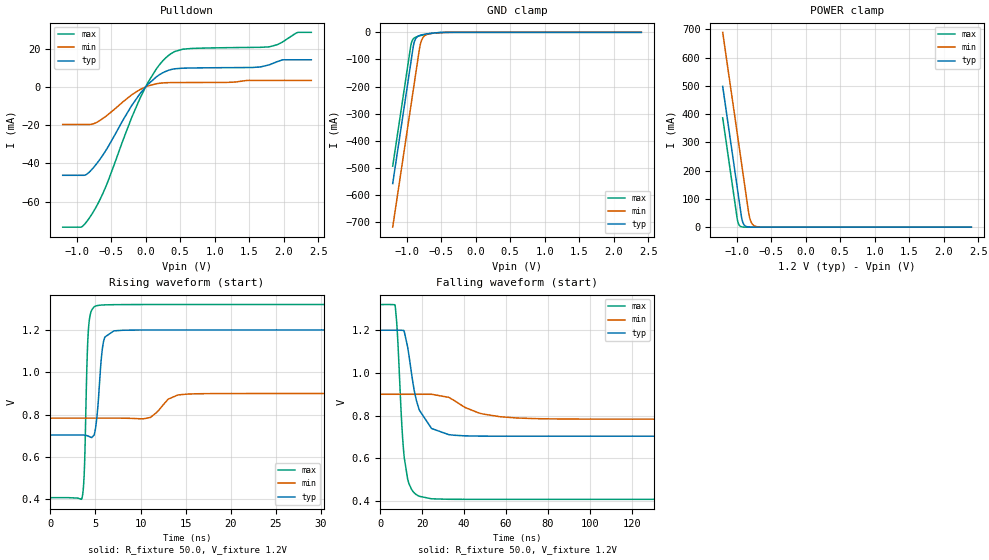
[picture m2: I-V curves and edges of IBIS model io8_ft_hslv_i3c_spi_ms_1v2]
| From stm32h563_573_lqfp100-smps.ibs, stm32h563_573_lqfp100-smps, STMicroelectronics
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[Model]   io8_ft_hslv_i3c_spi_ms_1v2
Model_type I/O_open_drain
Polarity   Non-Inverting
Enable   Active-Low
| CAP_THRESHOLD on pad IOFT is "UDTCAPC" :
| Rising=20.0% of vddiom   Falling=80.0% of vddiom
| C_comp min and max val. don't necessarily correlate with the min and max pvt
| but are the smallest and greatest pad capacitance found.
| var   typ   min   max
C_comp   3.41800pF  3.39985pF  3.42900pF
|C_comp_pulldown   3.41800pF  3.39985pF  3.42900pF
Vinl = 450.0mV
Vinh = 660.0mV
Vmeas = 600.0mV   | Reference voltage for timing measurements
Cref  = 50.0pF   | Timing specification test load capacitance value
Rref  = 1.0MOhm   | Timing specification test load resistance value
Vref  = 660.0mV   | Timing specification test load voltage
[Model Spec]
| TIME_THRESHOLD on pin ZII2CV11 is "CMOS" :
| Rising=40.0% of vdd   Falling=60.0% of vdd
Vinl 447.80000mV 344.80000mV 489.80000mV
Vinh 733.20000mV 535.20000mV 813.20000mV
| variable   typ   min   max
[Temperature Range] 25.0 125.0 -40.0
| variable   typ   min   max
[Voltage Range] 1.2V 900.0mV 1.32V
| variable   typ   min   max
[POWER Clamp Reference] 1.2V 900.0mV 1.32V
| variable   typ   min   max
[GND Clamp Reference] 0V 0V 0V
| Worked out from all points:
|   slope of the pulldown table from 0 to 0.18 V, typ, clamps not added: 30.6 ohm
|   GND clamp passes 1 mA (typ) near -0.52 V on its own axis
|   POWER clamp passes 1 mA (typ) near -0.84 V on its own axis
|   rising waveform, R_fixture 50.0, V_fixture 1.2V: 20-80 % time 543ps typ, 1.57ns min, 328ps max; typ from 0.704 V to 1.2 V
|   falling waveform, R_fixture 50.0, V_fixture 1.2V: 20-80 % time 6.81ns typ, 15.3ns min, 3.22ns max; typ from 1.2 V to 0.704 V
[POWER Clamp]
-1.2V     497.8mA    689.2mA    386.5mA
-990mV    140.8mA    332.2mA    29.53mA
-980mV    123.8mA    315.2mA    17.95mA
-960mV    89.81mA    281.2mA    6.634mA
-930mV    38.81mA    230.2mA    1.49mA
-900mV    12.07mA    179.2mA    334.8uA
-870mV    3.756mA    128.2mA    75.22uA
-820mV    536.4uA    44.98mA    6.246uA
-790mV    166.9uA    18.76mA    1.403uA
-750mV    35.18uA    5.846mA    191.8nA
-590mV    70.09nA    55uA       165.5pA
2.4V      0A         0A         0A
[GND Clamp]
-1.2V     -558.2mA   -719mA     -494.1mA
-940mV    -116.2mA   -277mA     -52.06mA
-930mV    -99.19mA   -260mA     -39.94mA
-900mV    -49.1mA    -209mA     -23.76mA
-880mV    -30.14mA   -175mA     -19.6mA
-850mV    -17.82mA   -124mA     -16.09mA
-810mV    -11.73mA   -56.78mA   -12.91mA
-780mV    -9.444mA   -28.21mA   -10.92mA
-740mV    -7.291mA   -13.16mA   -8.574mA
-640mV    -3.573mA   -4.171mA   -3.954mA
-380mV    -61.75uA   -230.3uA   -20.32uA
2.4V      3.863nA    718.4nA    150.6pA
| variable   typ   min   max
[Pullup Reference] 1.2V 900.0mV 1.32V
| variable   typ   min   max
[Pulldown Reference] 0V 0V 0V
[Pulldown]
-1.2V     -46.17mA   -19.62mA   -73.27mA
-930mV    -46.17mA   -19.62mA   -73.18mA
-770mV    -42.8mA    -19.41mA   -66.04mA
-570mV    -32.88mA   -15.18mA   -51.58mA
-80mV     -3.488mA   -1.363mA   -5.887mA
160mV     5.368mA    1.686mA    9.621mA
340mV     8.782mA    2.251mA    16.66mA
540mV     9.805mA    2.305mA    19.74mA
1.79V     11.53mA    3.428mA    20.94mA
1.98V     14.11mA    3.428mA    23.43mA
2.2V      14.2mA     3.428mA    28.44mA
2.4V      14.2mA     3.428mA    28.54mA
[Ramp]
dV/dt_r 297.78941mV/542.92947ps 69.89228mV/1.49795ns 547.1275mV/326.08305ps
dV/dt_f 297.80517mV/6.15576ns 69.92038mV/15.00937ns 547.13932mV/3.15836ns
R_load = 50.0
| Removed startup time: 0s 0s 0s  .
| Removed end time: 49.4ns.
[Rising Waveform]
R_fixture   = 50.0
V_fixture   = 1.2V
V_fixture_min = 900.0mV
V_fixture_max = 1.32V
0s        703.7mV    783.5mV    408.1mV
3.55ns    703.8mV    783.5mV    412.2mV
3.8ns     703.2mV    783.5mV    565.1mV
4.05ns    701.1mV    783.5mV    1.018V
4.2ns     698.8mV    783.5mV    1.184V
5ns       731.9mV    783.5mV    1.312V
5.85ns    1.133V     783.5mV    1.318V
7.05ns    1.196V     783.5mV    1.319V
15.15ns   1.2V       896.9mV    1.32V
49.4ns    1.2V       900mV      1.32V
| Removed startup time: 0s 0s 0s  .
| Removed end time: 399.4ns.
[Falling Waveform]
R_fixture   = 50.0
V_fixture   = 1.2V
V_fixture_min = 900.0mV
V_fixture_max = 1.32V
0s        1.2V       900mV      1.32V
7.05ns    1.2V       900mV      1.317V
8.05ns    1.2V       900mV      1.203V
10.15ns   1.2V       900mV      777.9mV
11.45ns   1.193V     900mV      602.3mV
13.75ns   1.077V     900mV      479.5mV
18.55ns   827.1mV    900mV      422.4mV
24.45ns   739.8mV    900mV      410.5mV
40.75ns   705.3mV    836.9mV    408.1mV
399.4ns   703.7mV    783.5mV    408.1mV
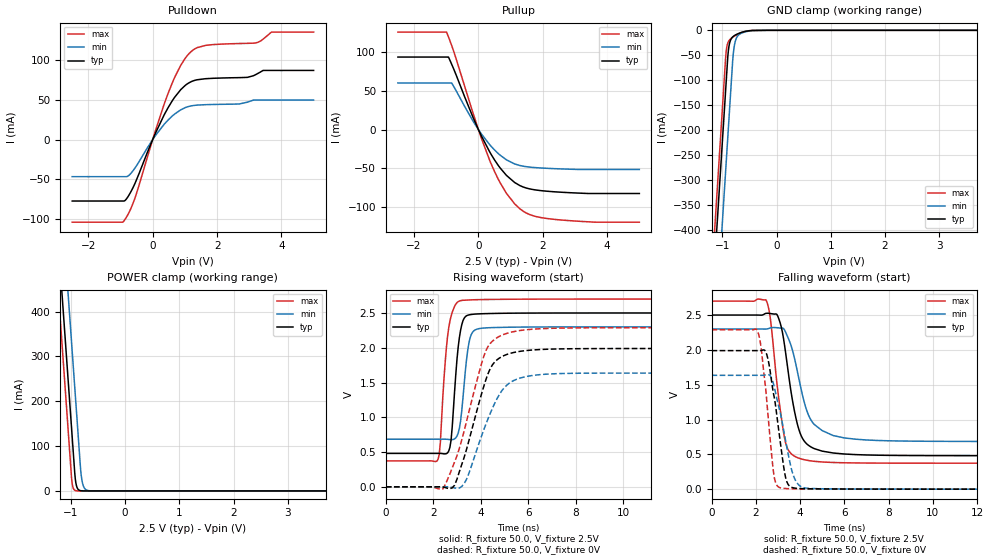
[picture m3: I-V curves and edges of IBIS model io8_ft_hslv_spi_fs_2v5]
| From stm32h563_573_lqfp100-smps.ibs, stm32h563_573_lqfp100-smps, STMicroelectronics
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[Model]   io8_ft_hslv_spi_fs_2v5
Model_type I/O
Polarity   Non-Inverting
Enable   Active-Low
| CAP_THRESHOLD on pad IOFT is "UDTCAPC" :
| Rising=20.0% of vddiom   Falling=80.0% of vddiom
| C_comp min and max val. don't necessarily correlate with the min and max pvt
| but are the smallest and greatest pad capacitance found.
| var   typ   min   max
C_comp   4.85188pF  4.77592pF  4.93402pF
|C_comp_pullup   3.10525pF  2.91265pF  2.94055pF
|C_comp_pulldown   1.74663pF  1.86327pF  1.99347pF
Vinl = 690.0mV
Vinh = 1.89V
Vmeas = 1.25V   | Reference voltage for timing measurements
Cref  = 50.0pF   | Timing specification test load capacitance value
Rref  = 100.0MOhm   | Timing specification test load resistance value
Vref  = 1.25V   | Timing specification test load voltage
[Model Spec]
| TIME_THRESHOLD on pin ZIV11 is "CMOS" :
| Rising=40.0% of vdd   Falling=60.0% of vdd
Vinl 989.80000mV 917.80000mV 1.06580V
Vinh 1.40320V 1.29620V 1.49120V
| variable   typ   min   max
[Temperature Range] 25.0 125.0 -40.0
| variable   typ   min   max
[Voltage Range] 2.5V 2.3V 2.7V
| variable   typ   min   max
[POWER Clamp Reference] 2.5V 2.3V 2.7V
| variable   typ   min   max
[GND Clamp Reference] 0V 0V 0V
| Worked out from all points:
|   slope of the pulldown table from 0 to 0.375 V, typ, clamps not added: 11.5 ohm
|   slope of the pullup table from 0 to 0.375 V, typ, clamps not added: 12.3 ohm
|   GND clamp passes 1 mA (typ) near -0.52 V on its own axis
|   POWER clamp passes 1 mA (typ) near -0.84 V on its own axis
|   rising waveform, R_fixture 50.0, V_fixture 2.5V: 20-80 % time 279ps typ, 288ps min, 300ps max; typ from 0.481 V to 2.5 V
|   falling waveform, R_fixture 50.0, V_fixture 2.5V: 20-80 % time 637ps typ, 796ps min, 509ps max; typ from 2.5 V to 0.481 V
|   rising waveform, R_fixture 50.0, V_fixture 0V: 20-80 % time 995ps typ, 1.12ns min, 1.08ns max; typ from 0 V to 1.99 V
|   falling waveform, R_fixture 50.0, V_fixture 0V: 20-80 % time 531ps typ, 636ps min, 417ps max; typ from 1.99 V to 0 V
[POWER Clamp]
-2.5V     2.708A     2.899A     2.597A
-1.23V    548.8mA    740.2mA    437.5mA
-1.16V    429.8mA    621.2mA    318.5mA
-1.07V    276.8mA    468.2mA    165.5mA
-1.03V    208.8mA    400.2mA    97.53mA
-980mV    123.8mA    315.2mA    17.95mA
-920mV    26.3mA     213.2mA    906uA
-880mV    5.543mA    145.2mA    123.7uA
-810mV    363.5uA    33.6mA     3.797uA
-770mV    76.62uA    10.47mA    518.9nA
-700mV    5.026uA    1.361mA    16.14nA
5V        0A         0A         0A
[GND Clamp]
-2.5V     -2.771A    -2.933A    -2.706A
-1.21V    -578.3mA   -739.7mA   -512.8mA
-950mV    -136.3mA   -297.7mA   -70.75mA
-930mV    -102.3mA   -263.7mA   -41.56mA
-900mV    -51.97mA   -212.7mA   -25.14mA
-880mV    -32.59mA   -178.7mA   -20.84mA
-850mV    -19.78mA   -127.7mA   -17.15mA
-810mV    -13.22mA   -60.17mA   -13.75mA
-780mV    -10.64mA   -30.96mA   -11.62mA
-730mV    -7.637mA   -13.21mA   -8.533mA
-430mV    -217.7uA   -562.2uA   -113.2uA
5V        7.27nA     1.305uA    342.4pA
| variable   typ   min   max
[Pullup Reference] 2.5V 2.3V 2.7V
| variable   typ   min   max
[Pulldown Reference] 0V 0V 0V
[Pullup]
-2.5V     93.6mA     60.17mA    125.8mA
-990mV    93.6mA     60.17mA    125.8mA
-930mV    93.6mA     60.17mA    119.6mA
-830mV    84.26mA    60.17mA    108.5mA
-170mV    16.03mA    11.13mA    21.65mA
350mV     -28.74mA   -19.44mA   -39.66mA
610mV     -45.85mA   -30.67mA   -63.5mA
870mV     -59.1mA    -39.02mA   -82.25mA
1.29V     -72.3mA    -46.39mA   -102.3mA
1.7V      -77.4mA    -48.84mA   -111.2mA
2.27V     -80.02mA   -50.27mA   -115.5mA
5V        -82.5mA    -51.48mA   -119.5mA
[Pulldown]
-2.5V     -77.63mA   -46.84mA   -104.3mA
-870mV    -77.25mA   -46.84mA   -101.4mA
-550mV    -55.3mA    -35.88mA   -73.72mA
90mV      8.401mA    5.299mA    11.79mA
610mV     49.03mA    29.76mA    71.69mA
870mV     62.92mA    37.48mA    93.62mA
1.23V     73.63mA    42.72mA    112.2mA
1.64V     76.78mA    44.01mA    118.8mA
2.94V     78.48mA    47.15mA    121.4mA
3.24V     82.82mA    49.81mA    122.4mA
3.69V     87.21mA    49.81mA    135.6mA
5V        87.21mA    49.81mA    135.6mA
[Ramp]
dV/dt_r 1.19345V/991.96714ps 980.81039mV/1.1152ns 1.37306V/1.07487ns
dV/dt_f 1.21165V/635.80001ps 969.25611mV/793.88244ps 1.39628V/507.94681ps
R_load = 50.0
| Removed startup time: 0s 0s 0s  .
| Removed end time: 14.4ns.
[Rising Waveform]
R_fixture   = 50.0
V_fixture   = 2.5V
V_fixture_min = 2.3V
V_fixture_max = 2.7V
0s        480.6mV    684.6mV    372.9mV
2.2ns     480.8mV    684.7mV    393.8mV
2.3ns     480.9mV    684.8mV    643.3mV
2.55ns    476.5mV    684.3mV    1.988V
2.7ns     566.2mV    679.1mV    2.381V
3.1ns     2.143V     838mV      2.672V
3.25ns    2.387V     1.271V     2.682V
3.5ns     2.472V     2.063V     2.687V
3.8ns     2.485V     2.262V     2.691V
14.4ns    2.5V       2.3V       2.7V
| Removed startup time: 0s 0s 0s  .
| Removed end time: 24.4ns.
[Falling Waveform]
R_fixture   = 50.0
V_fixture   = 2.5V
V_fixture_min = 2.3V
V_fixture_max = 2.7V
0s        2.5V       2.3V       2.7V
2.45ns    2.524V     2.299V     2.719V
2.65ns    2.522V     2.315V     2.466V
2.95ns    2.51V      2.318V     1.53V
3.3ns     2.062V     2.284V     730.3mV
3.7ns     1.197V     1.942V     482.9mV
4.05ns    766.9mV    1.432V     434.3mV
4.65ns    581.1mV    926.2mV    399.8mV
6.5ns     496.3mV    717.4mV    376.6mV
24.4ns    480.6mV    684.6mV    372.9mV
| Removed startup time: 0s 0s 0s  .
| Removed end time: 24.3ns.
[Rising Waveform]
R_fixture   = 50.0
V_fixture   = 0V
V_fixture_min = 0V
V_fixture_max = 0V
0s        101.5nV    479.1nV    83.45nV
2.4ns     -2.315mV   140.8uV    -31.1mV
2.9ns     23.63mV    -16.24mV   358mV
3.2ns     320.8mV    4.561mV    672.9mV
3.4ns     536.1mV    107.2mV    937.6mV
4.2ns     1.522V     884mV      1.944V
4.6ns     1.799V     1.208V     2.125V
5.2ns     1.914V     1.489V     2.217V
7.5ns     1.984V     1.63V      2.283V
24.3ns    1.989V     1.635V     2.288V
| Removed startup time: 0s 0s 0s  .
| Removed end time: 24.4ns.
[Falling Waveform]
R_fixture   = 50.0
V_fixture   = 0V
V_fixture_min = 0V
V_fixture_max = 0V
0s        1.989V     1.635V     2.288V
2.05ns    1.989V     1.635V     2.29V
2.25ns    1.992V     1.635V     2.005V
2.55ns    1.866V     1.645V     1.064V
2.85ns    1.289V     1.445V     143.8mV
3.1ns     689.6mV    1.106V     20.2mV
3.45ns    72.87mV    525mV      7.716mV
3.8ns     13.72mV    121.2mV    5.207mV
4.25ns    6.464mV    16.49mV    3.767mV
24.4ns    1.106uV    6.634uV    254.9nV
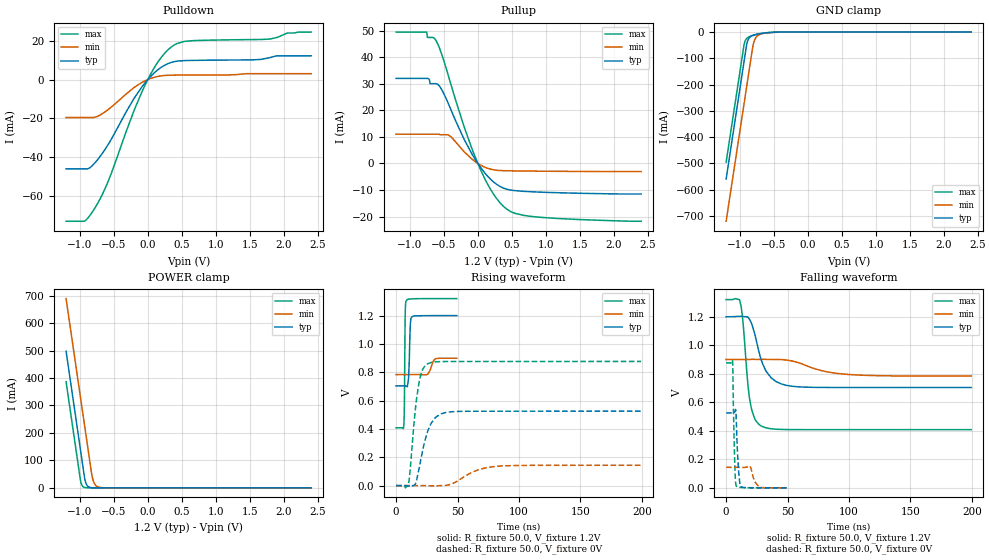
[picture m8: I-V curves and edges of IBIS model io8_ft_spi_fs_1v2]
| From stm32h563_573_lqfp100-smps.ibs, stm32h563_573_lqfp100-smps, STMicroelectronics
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[Model]   io8_ft_spi_fs_1v2
Model_type I/O
Polarity   Non-Inverting
Enable   Active-Low
| CAP_THRESHOLD on pad IOFT is "UDTCAPC" :
| Rising=20.0% of vddiom   Falling=80.0% of vddiom
| C_comp min and max val. don't necessarily correlate with the min and max pvt
| but are the smallest and greatest pad capacitance found.
| var   typ   min   max
C_comp   4.02965pF  3.92715pF  4.03450pF
|C_comp_pullup   2.45850pF  2.26975pF  2.18270pF
|C_comp_pulldown   1.57115pF  1.65740pF  1.85180pF
Vinl = 270.0mV
Vinh = 924.0mV
Vmeas = 600.0mV   | Reference voltage for timing measurements
Cref  = 50.0pF   | Timing specification test load capacitance value
Rref  = 100.0MOhm   | Timing specification test load resistance value
Vref  = 600.0mV   | Timing specification test load voltage
[Model Spec]
| TIME_THRESHOLD on pin ZIV11 is "CMOS" :
| Rising=40.0% of vdd   Falling=60.0% of vdd
Vinl 447.80000mV 344.80000mV 489.80000mV
Vinh 733.20000mV 535.20000mV 813.20000mV
| variable   typ   min   max
[Temperature Range] 25.0 125.0 -40.0
| variable   typ   min   max
[Voltage Range] 1.2V 900.0mV 1.32V
| variable   typ   min   max
[POWER Clamp Reference] 1.2V 900.0mV 1.32V
| variable   typ   min   max
[GND Clamp Reference] 0V 0V 0V
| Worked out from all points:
|   slope of the pulldown table from 0 to 0.18 V, typ, clamps not added: 30.6 ohm
|   slope of the pullup table from 0 to 0.18 V, typ, clamps not added: 31.3 ohm
|   GND clamp passes 1 mA (typ) near -0.52 V on its own axis
|   POWER clamp passes 1 mA (typ) near -0.84 V on its own axis
|   rising waveform, R_fixture 50.0, V_fixture 1.2V: 20-80 % time 1.04ns typ, 2.96ns min, 545ps max; typ from 0.704 V to 1.2 V
|   falling waveform, R_fixture 50.0, V_fixture 1.2V: 20-80 % time 11.3ns typ, 27.8ns min, 5.85ns max; typ from 1.2 V to 0.704 V
|   rising waveform, R_fixture 50.0, V_fixture 0V: 20-80 % time 9.19ns typ, 18.9ns min, 6.12ns max; typ from 0 V to 0.525 V
|   falling waveform, R_fixture 50.0, V_fixture 0V: 20-80 % time 1.83ns typ, 3.74ns min, 1.34ns max; typ from 0.525 V to 0 V
[POWER Clamp]
-1.2V     497.8mA    689.2mA    386.5mA
-990mV    140.8mA    332.2mA    29.53mA
-980mV    123.8mA    315.2mA    17.95mA
-960mV    89.81mA    281.2mA    6.634mA
-930mV    38.81mA    230.2mA    1.49mA
-900mV    12.07mA    179.2mA    334.8uA
-870mV    3.756mA    128.2mA    75.22uA
-820mV    536.4uA    44.98mA    6.246uA
-790mV    166.9uA    18.76mA    1.403uA
-750mV    35.18uA    5.846mA    191.9nA
-590mV    70.48nA    54.99uA    204.6pA
2.4V      0A         0A         0A
[GND Clamp]
-1.2V     -559.6mA   -720.6mA   -495.5mA
-940mV    -117.6mA   -278.6mA   -53.46mA
-930mV    -100.6mA   -261.6mA   -41.27mA
-900mV    -50.49mA   -210.6mA   -24.86mA
-880mV    -31.4mA    -176.6mA   -20.57mA
-850mV    -18.9mA    -125.6mA   -16.88mA
-810mV    -12.57mA   -58.3mA    -13.49mA
-780mV    -10.11mA   -29.57mA   -11.38mA
-740mV    -7.754mA   -14.31mA   -8.91mA
-640mV    -3.713mA   -4.821mA   -4.078mA
-390mV    -82.2uA    -288.6uA   -29.73uA
2.4V      3.859nA    727.3nA    172.3pA
| variable   typ   min   max
[Pullup Reference] 1.2V 900.0mV 1.32V
| variable   typ   min   max
[Pulldown Reference] 0V 0V 0V
[Pullup]
-1.2V     32.05mA    11.03mA    49.51mA
-750mV    32.05mA    11.03mA    49.51mA
-740mV    32.05mA    11.03mA    47.48mA
-620mV    30.06mA    11.03mA    46.54mA
-540mV    28.24mA    10.83mA    41.88mA
-420mV    21.78mA    10.54mA    31.99mA
-200mV    9.064mA    4.395mA    13.74mA
0V        7.46pA     726pA      4.231pA
210mV     -6.479mA   -2.287mA   -10.71mA
410mV     -9.591mA   -2.737mA   -16.89mA
900mV     -10.8mA    -2.907mA   -20.25mA
2.4V      -11.52mA   -3.045mA   -21.79mA
[Pulldown]
-1.2V     -46.17mA   -19.62mA   -73.27mA
-930mV    -46.17mA   -19.62mA   -73.17mA
-770mV    -42.8mA    -19.41mA   -66.04mA
-570mV    -32.88mA   -15.18mA   -51.58mA
-200mV    -9.658mA   -4.083mA   -15.89mA
-80mV     -3.488mA   -1.363mA   -5.887mA
130mV     4.529mA    1.469mA    8.049mA
340mV     8.782mA    2.251mA    16.66mA
540mV     9.805mA    2.305mA    19.74mA
1.79V     11.29mA    3.028mA    20.92mA
2.05V     12.25mA    3.028mA    24.04mA
2.4V      12.25mA    3.028mA    24.55mA
[Ramp]
dV/dt_r 315.14885mV/9.02639ns 86.08848mV/18.8141ns 525.77968mV/6.01221ns
dV/dt_f 297.79749mV/11.01382ns 69.89274mV/27.52837ns 547.13934mV/5.79008ns
R_load = 50.0
| Removed startup time: 0s 0s 0s  .
| Removed end time: 49.4ns.
[Rising Waveform]
R_fixture   = 50.0
V_fixture   = 1.2V
V_fixture_min = 900.0mV
V_fixture_max = 1.32V
0s        703.7mV    783.5mV    408.1mV
6.25ns    703.7mV    783.5mV    420.7mV
6.75ns    703.7mV    783.5mV    586.9mV
7.4ns     703.8mV    783.5mV    1.198V
8.05ns    702.5mV    783.5mV    1.302V
10.1ns    753.8mV    783.5mV    1.316V
11.55ns   1.131V     783.5mV    1.317V
13.1ns    1.194V     783.5mV    1.318V
32.3ns    1.2V       895.6mV    1.32V
49.4ns    1.2V       899.6mV    1.32V
| Removed startup time: 0s 0s 0s  .
| Removed end time: 199.4ns.
[Falling Waveform]
R_fixture   = 50.0
V_fixture   = 1.2V
V_fixture_min = 900.0mV
V_fixture_max = 1.32V
0s        1.2V       900mV      1.32V
11.05ns   1.203V     900mV      1.316V
13.4ns    1.202V     900mV      1.188V
19.2ns    1.179V     900.1mV    618.9mV
23.3ns    1.078V     901mV      483.4mV
28.5ns    899.3mV    900.8mV    434.1mV
36.65ns   771.4mV    900.2mV    414mV
52.9ns    713.2mV    891mV      408.4mV
97.7ns    703.7mV    796.3mV    408.1mV
199.4ns   703.7mV    783.5mV    408.1mV
| Removed startup time: 0s 0s 0s  .
| Removed end time: 199.4ns.
[Rising Waveform]
R_fixture   = 50.0
V_fixture   = 0V
V_fixture_min = 0V
V_fixture_max = 0V
0s        166.5nV    850.9nV    114.4nV
10.1ns    -2.776mV   1.168uV    13.51mV
15.4ns    7.483mV    564.2nV    515.4mV
18.8ns    125mV      2.103uV    735.6mV
21.8ns    256.5mV    44.08uV    822.5mV
25.9ns    388.5mV    -816.3uV   861.1mV
32.6ns    485.4mV    -1.757mV   874mV
44.8ns    521.1mV    9.33mV     876.1mV
81.4ns    525.1mV    135.7mV    876.2mV
199.4ns   525.2mV    143.5mV    876.3mV
| Removed startup time: 0s 0s 0s  .
| Removed end time: 49.4ns.
[Falling Waveform]
R_fixture   = 50.0
V_fixture   = 0V
V_fixture_min = 0V
V_fixture_max = 0V
0s        525.3mV    143.6mV    876.3mV
5.25ns    525.3mV    143.6mV    888.6mV
5.95ns    524.8mV    143.6mV    548.4mV
7.05ns    533.8mV    143.6mV    165.1mV
8.15ns    498mV      143.6mV    16.07mV
9.95ns    139.5mV    143.6mV    4.45mV
12.1ns    7.306mV    143.6mV    2.744mV
19.15ns   1.18mV     153mV      344.6uV
27.25ns   339.3uV    7.439mV    70.62uV
49.4ns    21.3uV     246.4uV    1.019uV
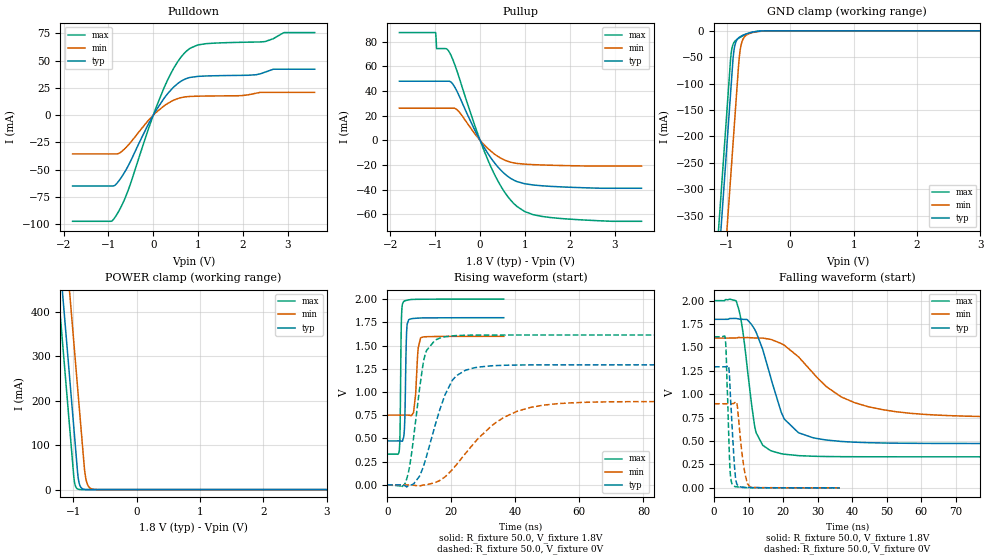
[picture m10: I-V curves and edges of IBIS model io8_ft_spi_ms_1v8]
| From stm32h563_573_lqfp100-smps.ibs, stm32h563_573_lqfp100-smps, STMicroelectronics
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[Model]   io8_ft_spi_ms_1v8
Model_type I/O
Polarity   Non-Inverting
Enable   Active-Low
| CAP_THRESHOLD on pad IOFT is "UDTCAPC" :
| Rising=20.0% of vddiom   Falling=80.0% of vddiom
| C_comp min and max val. don't necessarily correlate with the min and max pvt
| but are the smallest and greatest pad capacitance found.
| var   typ   min   max
C_comp   4.56197pF  4.45395pF  4.75004pF
|C_comp_pullup   2.85175pF  2.67185pF  2.77190pF
|C_comp_pulldown   1.71022pF  1.78210pF  1.97814pF
Vinl = 480.0mV
Vinh = 1.4V
Vmeas = 900.0mV   | Reference voltage for timing measurements
Cref  = 50.0pF   | Timing specification test load capacitance value
Rref  = 100.0MOhm   | Timing specification test load resistance value
Vref  = 900.0mV   | Timing specification test load voltage
[Model Spec]
| TIME_THRESHOLD on pin ZIV11 is "CMOS" :
| Rising=40.0% of vdd   Falling=60.0% of vdd
Vinl 703.80000mV 631.80000mV 784.80000mV
Vinh 1.06220V 937.20000mV 1.16620V
| variable   typ   min   max
[Temperature Range] 25.0 125.0 -40.0
| variable   typ   min   max
[Voltage Range] 1.8V 1.6V 2.0V
| variable   typ   min   max
[POWER Clamp Reference] 1.8V 1.6V 2.0V
| variable   typ   min   max
[GND Clamp Reference] 0V 0V 0V
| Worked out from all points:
|   slope of the pulldown table from 0 to 0.27 V, typ, clamps not added: 15.8 ohm
|   slope of the pullup table from 0 to 0.27 V, typ, clamps not added: 17.1 ohm
|   GND clamp passes 1 mA (typ) near -0.52 V on its own axis
|   POWER clamp passes 1 mA (typ) near -0.84 V on its own axis
|   rising waveform, R_fixture 50.0, V_fixture 1.8V: 20-80 % time 432ps typ, 883ps min, 325ps max; typ from 0.474 V to 1.8 V
|   falling waveform, R_fixture 50.0, V_fixture 1.8V: 20-80 % time 6.78ns typ, 16.6ns min, 3.39ns max; typ from 1.8 V to 0.474 V
|   rising waveform, R_fixture 50.0, V_fixture 0V: 20-80 % time 7.14ns typ, 15.4ns min, 3.62ns max; typ from 0 V to 1.29 V
|   falling waveform, R_fixture 50.0, V_fixture 0V: 20-80 % time 1.19ns typ, 1.68ns min, 840ps max; typ from 1.29 V to 0 V
[POWER Clamp]
-1.8V     1.518A     1.709A     1.407A
-1.23V    548.8mA    740.2mA    437.5mA
-1.16V    429.8mA    621.2mA    318.5mA
-1.05V    242.8mA    434.2mA    131.5mA
-980mV    123.8mA    315.2mA    17.95mA
-930mV    38.81mA    230.2mA    1.49mA
-910mV    17.82mA    196.2mA    550.8uA
-890mV    8.18mA     162.2mA    203.5uA
-810mV    363.5uA    33.6mA     3.797uA
-770mV    76.62uA    10.47mA    518.8nA
-710mV    7.417uA    1.822mA    26.38nA
3.6V      0A         0A         0A
[GND Clamp]
-1.8V     -1.581A    -1.742A    -1.516A
-1.24V    -628.8mA   -789.9mA   -564.1mA
-1.05V    -305.8mA   -466.9mA   -241.1mA
-940mV    -118.8mA   -279.9mA   -54.1mA
-930mV    -101.8mA   -262.9mA   -41.86mA
-900mV    -51.51mA   -211.9mA   -25.34mA
-880mV    -32.22mA   -177.9mA   -21mA
-810mV    -13.02mA   -59.5mA    -13.82mA
-770mV    -9.8mA     -24.99mA   -11mA
-680mV    -5.275mA   -7.288mA   -5.917mA
-400mV    -107uA     -349.1uA   -42.51uA
3.6V      5.392nA    968.2nA    261.3pA
| variable   typ   min   max
[Pullup Reference] 1.8V 1.6V 2.0V
| variable   typ   min   max
[Pulldown Reference] 0V 0V 0V
[Pullup]
-1.8V     48.01mA    26.14mA    87.55mA
-990mV    48.01mA    26.14mA    87.55mA
-970mV    48.01mA    26.14mA    74.54mA
-700mV    48.01mA    26.14mA    72.44mA
-490mV    37.91mA    24.03mA    53.53mA
-120mV    8.364mA    5.385mA    12.19mA
190mV     -11.56mA   -7.18mA    -17.34mA
510mV     -25.96mA   -15.42mA   -40.03mA
830mV     -33.6mA    -18.8mA    -53.95mA
1.18V     -36.29mA   -19.75mA   -60.37mA
1.56V     -37.38mA   -20.24mA   -62.7mA
3.6V      -38.97mA   -20.89mA   -65.81mA
[Pulldown]
-1.8V     -65.02mA   -35.56mA   -97.42mA
-940mV    -65.02mA   -35.56mA   -97.42mA
-850mV    -64.17mA   -35.56mA   -93.5mA
-570mV    -47.32mA   -28.01mA   -70.04mA
-120mV    -9.088mA   -5.279mA   -14.07mA
250mV     16.04mA    8.832mA    26.05mA
550mV     29.17mA    15.25mA    49.41mA
780mV     34.17mA    17.07mA    60.14mA
1.18V     35.97mA    17.56mA    65.65mA
2.49V     39.44mA    20.93mA    67.53mA
2.92V     42.19mA    20.93mA    75.82mA
3.6V      42.19mA    20.93mA    75.82mA
[Ramp]
dV/dt_r 775.80765mV/6.98776ns 538.89338mV/15.30917ns 968.32342mV/3.6162ns
dV/dt_f 795.78723mV/6.69799ns 508.97542mV/16.29603ns 1.00099V/3.38704ns
R_load = 50.0
| Removed startup time: 0s 0s 0s  .
| Removed end time: 36.4ns.
[Rising Waveform]
R_fixture   = 50.0
V_fixture   = 1.8V
V_fixture_min = 1.6V
V_fixture_max = 2.0V
0s        473.7mV    751.7mV    331.7mV
3.75ns    473.7mV    751.7mV    370mV
4ns       473.6mV    751.7mV    596.8mV
4.45ns    471.2mV    751.7mV    1.81V
5.15ns    518.4mV    751.7mV    1.976V
6.05ns    1.647V     751.8mV    1.987V
6.7ns     1.779V     751.2mV    1.991V
8.2ns     1.792V     777.5mV    1.997V
10.4ns    1.797V     1.582V     1.998V
36.4ns    1.8V       1.6V       2V
| Removed startup time: 0s 0s 0s  .
| Removed end time: 199.4ns.
[Falling Waveform]
R_fixture   = 50.0
V_fixture   = 1.8V
V_fixture_min = 1.6V
V_fixture_max = 2.0V
0s        1.8V       1.6V       2V
6.45ns    1.809V     1.601V     1.992V
8.1ns     1.8V       1.604V     1.729V
12.2ns    1.661V     1.601V     588.5mV
14.1ns    1.479V     1.6V       454.8mV
19.45ns   808.6mV    1.542V     365mV
24.65ns   586.4mV    1.392V     343.9mV
36.65ns   496.3mV    976.5mV    333.2mV
52.9ns    477.2mV    812.4mV    331.8mV
199.4ns   473.7mV    751.7mV    331.7mV
| Removed startup time: 0s 0s 0s  .
| Removed end time: 199.3ns.
[Rising Waveform]
R_fixture   = 50.0
V_fixture   = 0V
V_fixture_min = 0V
V_fixture_max = 0V
0s        134.8nV    547.1nV    93.88nV
5.7ns     -11.17mV   -463.7nV   26.47mV
7.1ns     -2.506mV   195.8uV    226.1mV
10ns      89.91mV    -11.86mV   1.011V
11.8ns    254.6mV    347.5uV    1.399V
18ns      967.1mV    85.41mV    1.594V
24.4ns    1.234V     337.4mV    1.611V
36.6ns    1.288V     730.6mV    1.614V
48.8ns    1.292V     858.9mV    1.614V
199.3ns   1.293V     898.2mV    1.614V
| Removed startup time: 0s 0s 0s  .
| Removed end time: 36.4ns.
[Falling Waveform]
R_fixture   = 50.0
V_fixture   = 0V
V_fixture_min = 0V
V_fixture_max = 0V
0s        1.293V     898.3mV    1.614V
3.2ns     1.293V     898.3mV    1.609V
3.5ns     1.293V     898.3mV    1.438V
4.2ns     1.296V     898.3mV    622.4mV
4.6ns     1.1V       898.2mV    211.1mV
5.75ns    320.7mV    902.6mV    18.28mV
6.7ns     33.56mV    883.7mV    10.63mV
8.6ns     6.408mV    230.7mV    3.403mV
10.4ns    4.233mV    11.71mV    1.274mV
36.4ns    59.67uV    220.4uV    10.1uV
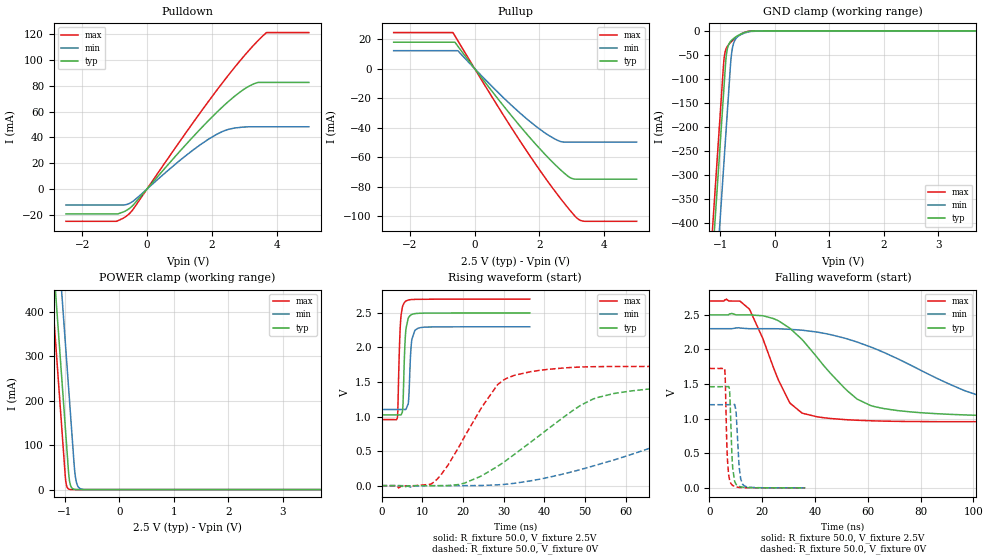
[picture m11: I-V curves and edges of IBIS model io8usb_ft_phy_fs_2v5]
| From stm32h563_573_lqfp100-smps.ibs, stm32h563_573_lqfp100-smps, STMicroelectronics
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[Model]   io8usb_ft_phy_fs_2v5
Model_type I/O
Polarity   Non-Inverting
Enable   Active-Low
| CAP_THRESHOLD on pad DPFT is "UDTCAPC" :
| Rising=20.0% of vddiom   Falling=80.0% of vddiom
| C_comp min and max val. don't necessarily correlate with the min and max pvt
| but are the smallest and greatest pad capacitance found.
| var   typ   min   max
C_comp   8.62848pF  8.50641pF  8.74957pF
|C_comp_pullup   5.79535pF  5.43185pF  5.42470pF
|C_comp_pulldown   2.83313pF  3.07456pF  3.32487pF
Vinl = 1.15V
Vinh = 1.35V
Vmeas = 1.25V   | Reference voltage for timing measurements
Cref  = 50.0pF   | Timing specification test load capacitance value
Rref  = 1.0MOhm   | Timing specification test load resistance value
Vref  = 1.375V   | Timing specification test load voltage
[Model Spec]
| TIME_THRESHOLD on pin ZIUSBPV11 is "CMOS" :
| Rising=40.0% of vdd   Falling=60.0% of vdd
Vinl 1.00380V 930.80000mV 1.08080V
Vinh 1.41920V 1.31220V 1.50720V
| variable   typ   min   max
[Temperature Range] 25.0 125.0 -40.0
| variable   typ   min   max
[Voltage Range] 2.5V 2.3V 2.7V
| variable   typ   min   max
[POWER Clamp Reference] 2.5V 2.3V 2.7V
| variable   typ   min   max
[GND Clamp Reference] 0V 0V 0V
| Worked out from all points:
|   slope of the pulldown table from 0 to 0.375 V, typ, clamps not added: 34.2 ohm
|   slope of the pullup table from 0 to 0.375 V, typ, clamps not added: 34.8 ohm
|   GND clamp passes 1 mA (typ) near -0.46 V on its own axis
|   POWER clamp passes 1 mA (typ) near -0.84 V on its own axis
|   rising waveform, R_fixture 50.0, V_fixture 2.5V: 20-80 % time 551ps typ, 584ps min, 557ps max; typ from 1.02 V to 2.5 V
|   falling waveform, R_fixture 50.0, V_fixture 2.5V: 20-80 % time 21.4ns typ, 42.1ns min, 11.5ns max; typ from 2.5 V to 1.02 V
|   rising waveform, R_fixture 50.0, V_fixture 0V: 20-80 % time 20.3ns typ, 38.5ns min, 10.7ns max; typ from 0 V to 1.46 V
|   falling waveform, R_fixture 50.0, V_fixture 0V: 20-80 % time 918ps typ, 1.17ns min, 838ps max; typ from 1.46 V to 0 V
[POWER Clamp]
-2.5V     2.708A     2.899A     2.597A
-1.29V    650.8mA    842.2mA    539.5mA
-1.2V     497.8mA    689.2mA    386.5mA
-1.18V    463.8mA    655.2mA    352.5mA
-1.12V    361.8mA    553.2mA    250.5mA
-1.05V    242.8mA    434.2mA    131.5mA
-980mV    123.8mA    315.2mA    17.95mA
-920mV    26.3mA     213.2mA    906uA
-810mV    363.5uA    33.6mA     3.797uA
-770mV    76.62uA    10.47mA    519.1nA
-700mV    5.028uA    1.361mA    16.38nA
5V        0A         0A         0A
[GND Clamp]
-2.5V     -2.787A    -2.944A    -2.726A
-1.21V    -594.3mA   -750.5mA   -532.8mA
-950mV    -152.3mA   -308.5mA   -90.81mA
-920mV    -101.3mA   -257.5mA   -50.71mA
-890mV    -54.53mA   -206.5mA   -37.29mA
-870mV    -38.94mA   -172.5mA   -32.93mA
-810mV    -22.25mA   -70.52mA   -24.51mA
-790mV    -19.71mA   -47.2mA    -22.19mA
-730mV    -14.01mA   -19.62mA   -15.92mA
-620mV    -6.579mA   -7.865mA   -6.951mA
-170mV    -138nA     -5.049uA   -5.744nA
5V        18.26nA    2.956uA    720.9pA
| variable   typ   min   max
[Pullup Reference] 2.5V 2.3V 2.7V
| variable   typ   min   max
[Pulldown Reference] 0V 0V 0V
[Pullup]
-2.5V     17.9mA     12.16mA    24.42mA
-670mV    17.9mA     12.16mA    24.42mA
-610mV    17.9mA     12.16mA    22.21mA
-520mV    15.23mA    12.16mA    18.91mA
870mV     -24.64mA   -19.28mA   -30.89mA
1.9V      -51.56mA   -39.21mA   -65.29mA
2.61V     -67.65mA   -49mA      -86.75mA
2.92V     -73.42mA   -49.7mA    -95.29mA
3.12V     -74.81mA   -49.7mA    -100.4mA
3.24V     -74.82mA   -49.7mA    -102.4mA
3.38V     -74.82mA   -49.7mA    -103.3mA
5V        -74.82mA   -49.7mA    -103.3mA
[Pulldown]
-2.5V     -19.26mA   -12.36mA   -24.99mA
-940mV    -19.26mA   -12.36mA   -24.99mA
-620mV    -16.33mA   -11.9mA    -20.72mA
-410mV    -12.02mA   -9.111mA   -15.08mA
1.38V     39.35mA    29.43mA    49.95mA
2.16V     59.59mA    42.52mA    76.74mA
2.5V      67.55mA    46.16mA    87.84mA
2.93V     76.24mA    47.93mA    101.1mA
3.24V     80.88mA    48.26mA    110mA
3.47V     82.67mA    48.26mA    116.1mA
3.69V     82.67mA    48.26mA    121.3mA
5V        82.67mA    48.26mA    121.3mA
[Ramp]
dV/dt_r 877.15745mV/20.22184ns 721.07436mV/38.35201ns 1.03539V/10.48717ns
dV/dt_f 885.63673mV/21.18833ns 717.5709mV/41.99745ns 1.04623V/10.95117ns
R_load = 50.0
| Removed startup time: 0s 0s 0s  .
| Removed end time: 36.4ns.
[Rising Waveform]
R_fixture   = 50.0
V_fixture   = 2.5V
V_fixture_min = 2.3V
V_fixture_max = 2.7V
0s        1.024V     1.103V     956.3mV
3.85ns    1.024V     1.103V     976.3mV
4.7ns     1.023V     1.103V     2.398V
5.25ns    1.159V     1.103V     2.608V
5.65ns    1.916V     1.102V     2.652V
5.95ns    2.241V     1.103V     2.672V
6.65ns    2.435V     1.241V     2.688V
7.35ns    2.476V     2.07V      2.694V
8.2ns     2.49V      2.25V      2.696V
36.4ns    2.5V       2.3V       2.7V
| Removed startup time: 0s 0s 0s  .
| Removed end time: 249.35ns.
[Falling Waveform]
R_fixture   = 50.0
V_fixture   = 2.5V
V_fixture_min = 2.3V
V_fixture_max = 2.7V
0s        2.5V       2.3V       2.7V
11.55ns   2.5V       2.312V     2.699V
15.25ns   2.5V       2.3V       2.582V
30.55ns   2.306V     2.291V     1.225V
40.7ns    1.893V     2.252V     1.028V
56ns      1.283V     2.107V     977mV
71.25ns   1.117V     1.868V     961mV
96.7ns    1.054V     1.405V     956.5mV
117.1ns   1.034V     1.237V     956.3mV
249.3ns   1.024V     1.104V     956.3mV
| Removed startup time: 0s 0s 0s  .
| Removed end time: 199.4ns.
[Rising Waveform]
R_fixture   = 50.0
V_fixture   = 0V
V_fixture_min = 0V
V_fixture_max = 0V
0s        15.59nV    1.077uV    10.15nV
12.5ns    -588.2uV   -504uV     36.07mV
20.4ns    37.3mV     7.319uV    711.9mV
28.5ns    279.4mV    11.4mV     1.463V
38.6ns    717.9mV    91.11mV    1.667V
48.9ns    1.164V     233.9mV    1.717V
57ns      1.333V     370.7mV    1.725V
97.7ns    1.461V     1.072V     1.726V
128.4ns   1.462V     1.184V     1.726V
199.4ns   1.462V     1.202V     1.726V
| Removed startup time: 0s 0s 0s  .
| Removed end time: 36.35ns.
[Falling Waveform]
R_fixture   = 50.0
V_fixture   = 0V
V_fixture_min = 0V
V_fixture_max = 0V
0s        1.462V     1.202V     1.726V
5.8ns     1.462V     1.202V     1.718V
6.9ns     1.462V     1.202V     408mV
7.75ns    1.376V     1.202V     109mV
8.45ns    618.5mV    1.202V     51.19mV
8.9ns     284.9mV    1.202V     35.03mV
10.1ns    55.09mV    1.126V     14.84mV
11.35ns   21.13mV    298.7mV    6.598mV
12.65ns   10.25mV    50.6mV     3.218mV
36.35ns   317.1uV    283.9uV    122.8uV
